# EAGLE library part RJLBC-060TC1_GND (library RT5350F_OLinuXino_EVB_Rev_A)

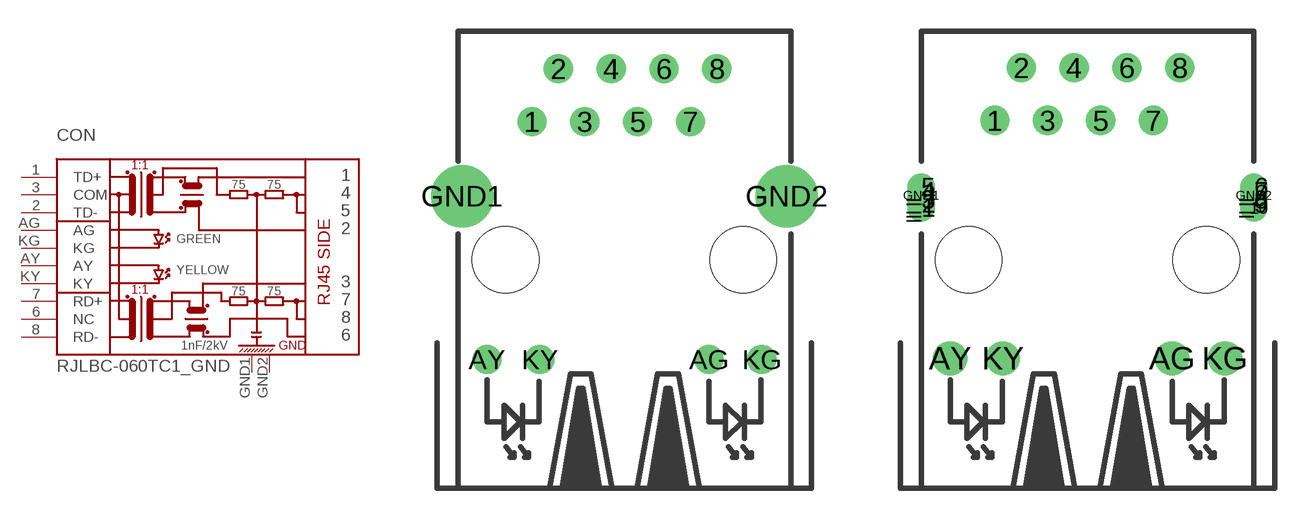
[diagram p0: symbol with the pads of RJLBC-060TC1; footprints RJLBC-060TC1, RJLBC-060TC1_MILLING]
Designator prefix CON

## RJLBC-060TC1_GND  [RJLBC-060TC1]
1  TD+
2  TD-
3  COM
6  NC
7  RD+
8  RD-
AG  AG  pas
AY  AY  pas
GND1  GND1  in
GND2  GND2  in
KG  KG  pas
KY  KY  pas

## RJLBC-060TC1_GND_MILLING  [RJLBC-060TC1_MILLING]
Pads as for RJLBC-060TC1

## Footprint RJLBC-060TC1 (pad centres in mm)
LAN traf & connector
drill 0.9: 1 -4.445,6.65; 2 -3.175,9.19; 3 -1.905,6.65; 4 -0.635,9.19; 5 0.635,6.65; 6 1.905,9.19; 7 3.175,6.65; 8 4.445,9.19; AG 4.07,-4.8; AY -6.61,-4.8; KG 6.61,-4.8; KY -4.07,-4.8
drill 2: GND1 -7.8,3.05; GND2 7.8,3.05
hole 3.2 at -5.715,0
hole 3.2 at 5.715,0
hole 3.2 at -5.715,0
hole 3.2 at 5.715,0

## Footprint RJLBC-060TC1_MILLING (pad centres in mm)
drill 0.9: 1 -4.455,6.7; 2 -3.185,9.24; 3 -1.915,6.7; 4 -0.645,9.24; 5 0.625,6.7; 6 1.895,9.24; 7 3.165,6.7; 8 4.435,9.24
drill 0.8: _1 -8,2.5; _2 -8,2.7; _3 -8,2.9; _4 -8,3.3; _5 -8,3.5; _6 8,3.5; _7 8,3.3; _8 8,2.9; _9 8,2.7; _10 8,2.5; GND1 -8,3.1; GND2 8,3.1
drill 1.1: AG 4.07,-4.748; AY -6.61,-4.748; KG 6.61,-4.748; KY -4.07,-4.748
hole 3.2 at -5.715,0
hole 3.2 at 5.715,0
hole 3.2 at -5.715,0
hole 3.2 at 5.715,0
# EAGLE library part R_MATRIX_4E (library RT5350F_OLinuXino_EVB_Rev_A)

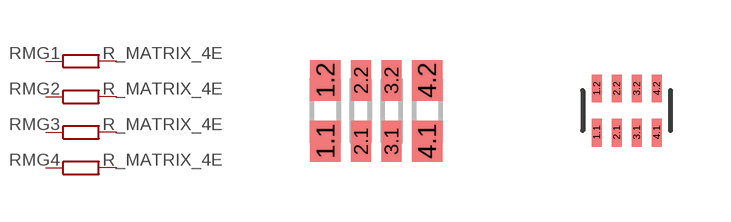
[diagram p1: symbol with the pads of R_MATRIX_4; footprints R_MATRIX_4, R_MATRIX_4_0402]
Designator prefix RM; gates G1=R_MARTIX G2=R_MARTIX G3=R_MARTIX G4=R_MARTIX

## R_MATRIX_4E  [R_MATRIX_4]
1.1  G1:1  pas
1.2  G1:2  pas
2.1  G2:1  pas
2.2  G2:2  pas
3.1  G3:1  pas
3.2  G3:2  pas
4.1  G4:1  pas
4.2  G4:2  pas

## R_MATRIX_4ER_MATRIX_4_0402  [R_MATRIX_4_0402]
Pads as for R_MATRIX_4

## R_MATRIX_4E_25X625  [R_MATRIX_4_0402_25X625]
Pads as for R_MATRIX_4

## R_MATRIX_4E_25X625_0R  [R_MATRIX_4_0402_25_625_0R]
Pads as for R_MATRIX_4

## Footprint R_MATRIX_4 (pad centres in mm)
Rotated counterclockwise 90 by Penko to ba as is in the real reel
smd 0.762 x 1.016: 1.1 -1.27,-0.762; 1.2 -1.27,0.762; 4.1 1.27,-0.762; 4.2 1.27,0.762
smd 0.508 x 1.016: 2.1 -0.381,-0.762; 2.2 -0.381,0.762; 3.1 0.381,-0.762; 3.2 0.381,0.762

## Footprint R_MATRIX_4_0402 (pad centres in mm)
Rotated counterclockwise 90 by Penko to ba as is in the real reel
smd 0.25 x 0.7: 1.1 -0.75,-0.55; 1.2 -0.75,0.55; 2.1 -0.25,-0.55; 2.2 -0.25,0.55; 3.1 0.25,-0.55; 3.2 0.25,0.55; 4.1 0.75,-0.55; 4.2 0.75,0.55

## Footprint R_MATRIX_4_0402_25X625 (pad centres in mm)
Rotated counterclockwise 90 by Penko to ba as is in the real reel
smd 0.25 x 0.625: 1.1 -0.75,-0.512; 1.2 -0.75,0.512; 2.1 -0.25,-0.512; 2.2 -0.25,0.512; 3.1 0.25,-0.512; 3.2 0.25,0.512; 4.1 0.75,-0.512; 4.2 0.75,0.512

## Footprint R_MATRIX_4_0402_25_625_0R (pad centres in mm)
Rotated counterclockwise 90 by Penko to ba as is in the real reel
smd 0.25 x 0.625: 1.1 -0.75,-0.512; 1.2 -0.75,0.512; 2.1 -0.25,-0.512; 2.2 -0.25,0.512; 3.1 0.25,-0.512; 3.2 0.25,0.512; 4.1 0.75,-0.512; 4.2 0.75,0.512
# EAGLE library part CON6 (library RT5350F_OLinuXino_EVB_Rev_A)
CONNECTORS - 6 PINS

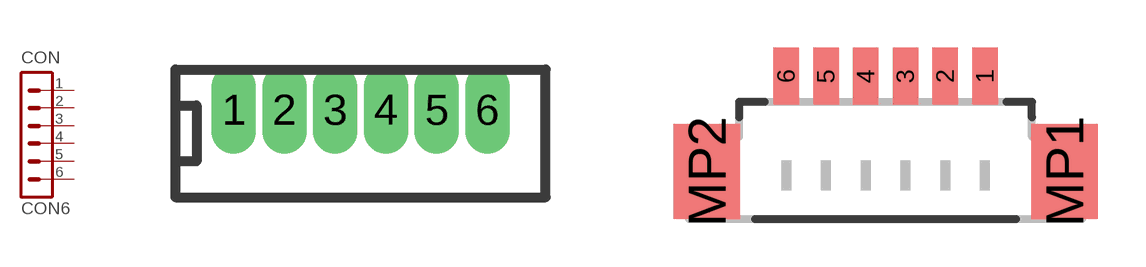
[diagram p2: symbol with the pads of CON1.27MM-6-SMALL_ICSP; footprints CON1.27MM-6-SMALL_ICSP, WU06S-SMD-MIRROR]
Designator prefix CON

## CON6  [CON1.27MM-6-SMALL_ICSP]
1  1  pas
2  2  pas
3  3  pas
4  4  pas
5  5  pas
6  6  pas

## CON6-WU06S-SMD  [WU06S-SMD-MIRROR]
Pads as for CON1.27MM-6-SMALL_ICSP

## CON61.27MM-6-SMALL  [CON1.27MM-6-SMALL_TRANSITIVE]
Pads as for CON1.27MM-6-SMALL_ICSP

## CON62.54-0-D  [CON2.54MM-6-0D]
Pads as for CON1.27MM-6-SMALL_ICSP

## CON6HD-515R_6P  [HD-515R_6P]
Pads as for CON1.27MM-6-SMALL_ICSP

## CON6HN1X6  [HN1X6]
Pads as for CON1.27MM-6-SMALL_ICSP

## CON6HN1X6-2.0(HN1X20-2.0)  [HN1X6-2.0]
Pads as for CON1.27MM-6-SMALL_ICSP

## CON6PN1X6  [PN1X6]
Pads as for CON1.27MM-6-SMALL_ICSP

## CON6PR6-3.96MM  [CON3.96MM-6-90]
Pads as for CON1.27MM-6-SMALL_ICSP

## CON6PV6-2.54MM  [CON2.54MM-6-0]
Pads as for CON1.27MM-6-SMALL_ICSP

## CON6PV6-3.96MM  [CON3.96MM-6-0]
Pads as for CON1.27MM-6-SMALL_ICSP

## CON6TDOCU  [CON6_TDOCU]
Pads as for CON1.27MM-6-SMALL_ICSP

## CON6TELEFON  [CON_TELEFON]
Pads as for CON1.27MM-6-SMALL_ICSP

## CON6WF6R  [WF6R]
Pads as for CON1.27MM-6-SMALL_ICSP

## CON6WF6S  [WF6S]
Pads as for CON1.27MM-6-SMALL_ICSP

## CON6WU06S-SMD  [WU06S-SMD]
Pads as for CON1.27MM-6-SMALL_ICSP

## CON6WUO6S  [WU06S]
Pads as for CON1.27MM-6-SMALL_ICSP

## Footprint CON1.27MM-6-SMALL_ICSP (pad centres in mm)
drill 0.6 pad 1.016 long: 1 -3.175,0; 2 -1.905,0; 3 -0.635,0; 4 0.635,0; 5 1.905,0; 6 3.175,0

## Footprint WU06S-SMD-MIRROR (pad centres in mm)
CI44 Series 1.25mm(.049") Pin Header Manifacture: CviLux, CI44 Series, Part Number: CI4406M1V00-LF Supplier: Comet Electronics Part Number: WU06S-SMD This is Male connector! It reqire SU06 Female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
smd 0.8 x 1.8: 1 3.125,0; 2 1.875,0; 3 0.625,0; 4 -0.625,0; 5 -1.875,0; 6 -3.125,0
smd 2.1 x 3: MP1 5.625,-3; MP2 -5.625,-3

## Footprint CON1.27MM-6-SMALL_TRANSITIVE (pad centres in mm)
drill 0.6 pad 1.016 long: 1 3.175,0; 2 1.905,0; 3 0.635,0; 4 -0.635,0; 5 -1.905,0; 6 -3.175,0

## Footprint CON2.54MM-6-0D (pad centres in mm)
drill 1.092 pad 1.778 square: 1 -6.35,0
drill 1.092 pad 1.778: 2 -3.81,0; 3 -1.27,0; 4 1.27,0; 5 3.81,0; 6 6.35,0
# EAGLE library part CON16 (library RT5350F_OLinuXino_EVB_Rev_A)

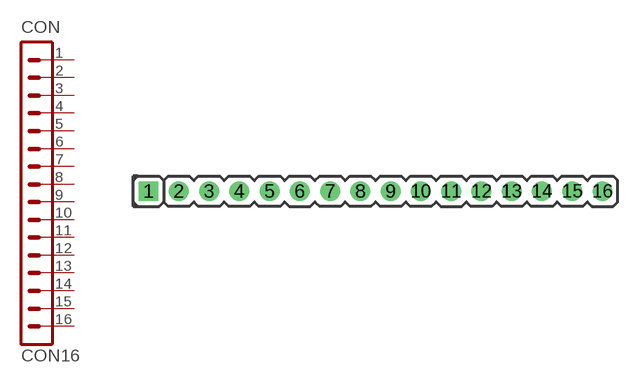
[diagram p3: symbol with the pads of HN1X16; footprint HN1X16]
Designator prefix CON

## CON16-HN1X16  [HN1X16]
1  1  pas
2  2  pas
3  3  pas
4  4  pas
5  5  pas
6  6  pas
7  7  pas
8  8  pas
9  9  pas
10  10  pas
11  11  pas
12  12  pas
13  13  pas
14  14  pas
15  15  pas
16  16  pas

## Footprint HN1X16 (pad centres in mm)
CH31 Series Manufacture: CviLux Supplier: Comet Electronics Part Number: HN1x16 is part of HN1x40 This is Male connector! It reqires PN1x16 Female connector Eletrical Characteristics: - 3A(per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
drill 1.016 pad 1.676 square: 1 -17.78,0
drill 1.016 pad 1.676: 2 -15.24,0; 3 -12.7,0; 4 -10.16,0; 5 -7.62,0; 6 -5.08,0; 7 -2.54,0; 8 0,0; 9 2.54,0; 10 5.08,0; 11 7.62,0; 12 10.16,0; 13 12.7,0; 14 15.24,0; 15 17.78,0; 16 20.32,0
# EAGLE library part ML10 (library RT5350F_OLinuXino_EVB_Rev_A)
HARTING

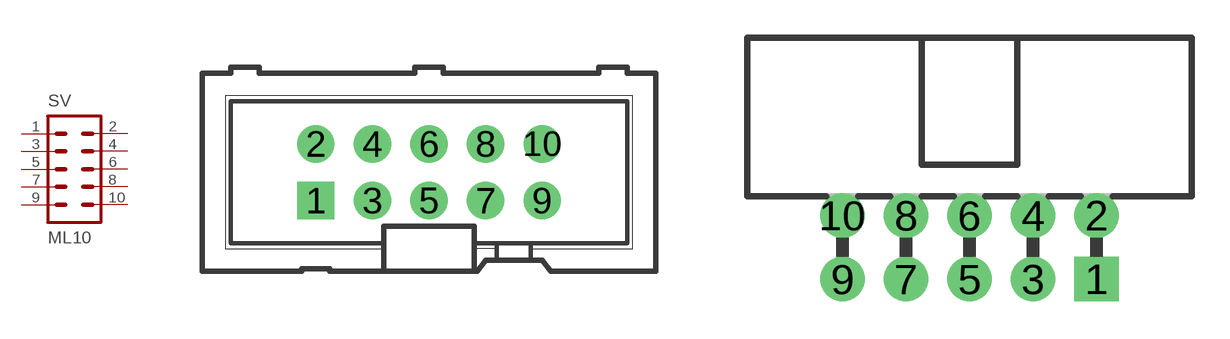
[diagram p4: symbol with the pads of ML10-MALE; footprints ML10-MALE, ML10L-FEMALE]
Designator prefix SV

## ML10  [ML10-MALE]
1  1  pas
2  2  pas
3  3  pas
4  4  pas
5  5  pas
6  6  pas
7  7  pas
8  8  pas
9  9  pas
10  10  pas

## ML10"  [ML10L-FEMALE]
Pads as for ML10-MALE

## ML10-3M  [3M_10]
Pads as for ML10-MALE

## ML10-3ML  [3M_10L]
Pads as for ML10-MALE

## ML10-GPH127SMT-02X05(PA-V16X-2X5-LF)  [GPH127SMT-02X05(PA-V16X-2X5-LF)]
Pads as for ML10-MALE

## ML10F50  [ML10_50MILS_F]
Pads as for ML10-MALE

## ML10L  [ML10L]
Pads as for ML10-MALE

## ML10M50  [ML10_50MILS_M]
Pads as for ML10-MALE

## ML10MD  [ML10_S]
Pads as for ML10-MALE

## ML10ML10-FEMALE  [ML10-FEMALE]
Pads as for ML10-MALE

## ML10ML10-FEMALE(IDC10S/PCB)  [ML10-FEMALE(IDC10S/PCB)]
Pads as for ML10-MALE

## ML10ML10M  [ML10_MIRROR]
Pads as for ML10-MALE

## ML10ML10_NEW  [ML10_NEW]
Pads as for ML10-MALE

## ML10PA-V16X-2X5-LF_0.60_DRILL  [PA-V16X-2X5-LF_0.60_DRILL]
Pads as for ML10-MALE

## ML10PA-V16X-2X5-LF_0.65_DRILL  [PA-V16X-2X5-LF_0.65_DRILL]
Pads as for ML10-MALE

## ML10R  [BH10R]
Pads as for ML10-MALE

## ML10SMD  [ML10_PADS]
Pads as for ML10-MALE

## ML10SMD_1  [ML10L_PADS_FEMAIL]
Pads as for ML10-MALE

## ML10YA-V36P-2X5-LF  [YA-V36P-2X5-LF]
Pads as for ML10-MALE

## ML10YA-V36P-2X5-LF_0.60_DRILL  [YA-V36P-2X5-LF_0.60_DRILL]
Pads as for ML10-MALE

## ML10YA-V36P-LF_0.65_DRILL  [YA-V36P-2X5-LF_0.65_DRILL]
Pads as for ML10-MALE

## Footprint ML10-MALE (pad centres in mm)
HARTING
drill 1.1 pad 1.676 square: 1 -5.08,-1.27
drill 1.1 pad 1.676: 2 -5.08,1.27; 3 -2.54,-1.27; 4 -2.54,1.27; 5 0,-1.27; 6 0,1.27; 7 2.54,-1.27; 8 2.54,1.27; 9 5.08,-1.27; 10 5.08,1.27

## Footprint ML10L-FEMALE (pad centres in mm)
drill 1 pad 1.778 square: 1 5.08,-6.35
drill 1 pad 1.778: 2 5.08,-3.81; 3 2.54,-6.35; 4 2.54,-3.81; 5 0,-6.35; 6 0,-3.81; 7 -2.54,-6.35; 8 -2.54,-3.81; 9 -5.08,-6.35; 10 -5.08,-3.81

## Footprint 3M_10 (pad centres in mm)
3M
drill 0.813 square: 1 -5.08,-1.27; 2 -5.08,1.27; 3 -2.54,-1.27; 4 -2.54,1.27; 5 0,-1.27; 6 0,1.27; 7 2.54,-1.27; 8 2.54,1.27; 9 5.08,-1.27; 10 5.08,1.27

## Footprint 3M_10L (pad centres in mm)
3M
drill 0.813 square: 1 -5.08,-5.08; 2 -5.08,-2.54; 3 -2.54,-5.08; 4 -2.54,-2.54; 5 0,-5.08; 6 0,-2.54; 7 2.54,-5.08; 8 2.54,-2.54; 9 5.08,-5.08; 10 5.08,-2.54
hole 2.54 at -10.998,-3.277
hole 2.54 at 10.998,-3.277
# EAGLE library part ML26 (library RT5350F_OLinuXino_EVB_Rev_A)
HARTING

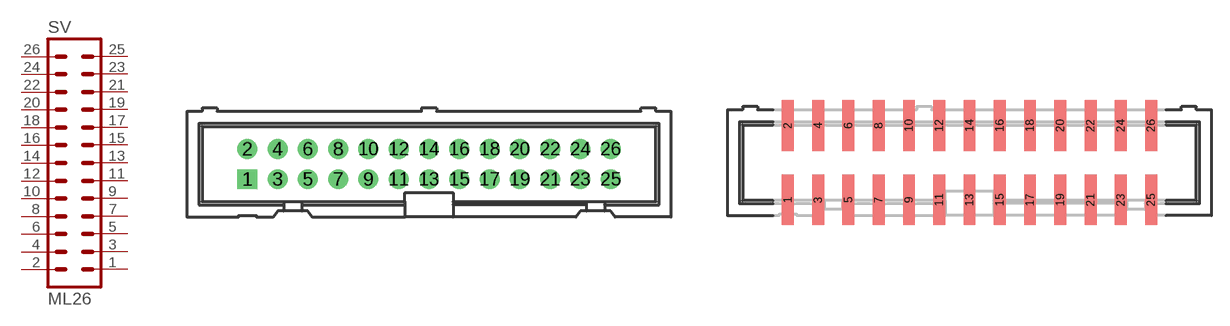
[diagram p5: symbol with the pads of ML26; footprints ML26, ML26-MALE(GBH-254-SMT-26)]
Designator prefix SV

## ML26  [ML26]
1  1  pas
2  2  pas
3  3  pas
4  4  pas
5  5  pas
6  6  pas
7  7  pas
8  8  pas
9  9  pas
10  10  pas
11  11  pas
12  12  pas
13  13  pas
14  14  pas
15  15  pas
16  16  pas
17  17  pas
18  18  pas
19  19  pas
20  20  pas
21  21  pas
22  22  pas
23  23  pas
24  24  pas
25  25  pas
26  26  pas

## ML26-(GBH-254-SMT-26)  [ML26-MALE(GBH-254-SMT-26)]
Pads as for ML26

## ML263M  [3M_26]
Pads as for ML26

## ML263ML  [3M_26L]
Pads as for ML26

## ML26HN2X13  [HN2X13-MALE]
Pads as for ML26

## ML26IDC26S/PCB  [ML26-FEMALE(IDC26S/PCB)]
Pads as for ML26

## ML26IDC26S/PCB_PADS  [ML26L_PADS-FEMALE(IDC26S/PCB)]
Pads as for ML26

## ML26L  [ML26L]
Pads as for ML26

## ML26PN2X13  [PN2X13]
Pads as for ML26

## ML26R  [BH26R]
Pads as for ML26

## Footprint ML26 (pad centres in mm)
HARTING
drill 1.016 pad 1.676 square: 1 -15.24,-1.27
drill 1.016 pad 1.676: 2 -15.24,1.27; 3 -12.7,-1.27; 4 -12.7,1.27; 5 -10.16,-1.27; 6 -10.16,1.27; 7 -7.62,-1.27; 8 -7.62,1.27; 9 -5.08,-1.27; 10 -5.08,1.27; 11 -2.54,-1.27; 12 -2.54,1.27; 13 0,-1.27; 14 0,1.27; 15 2.54,-1.27; 16 2.54,1.27; 17 5.08,-1.27; 18 5.08,1.27; 19 7.62,-1.27; 20 7.62,1.27; 21 10.16,-1.27; 22 10.16,1.27; 23 12.7,-1.27; 24 12.7,1.27; 25 15.24,-1.27; 26 15.24,1.27

## Footprint ML26-MALE(GBH-254-SMT-26) (pad centres in mm)
smd 1 x 4.25: 1 -15.24,-3.125; 2 -15.24,3.125; 3 -12.7,-3.125; 4 -12.7,3.125; 5 -10.16,-3.125; 6 -10.16,3.125; 7 -7.62,-3.125; 8 -7.62,3.125; 9 -5.08,-3.125; 10 -5.08,3.125; 11 -2.54,-3.125; 12 -2.54,3.125; 13 0,-3.125; 14 0,3.125; 15 2.54,-3.125; 16 2.54,3.125; 17 5.08,-3.125; 18 5.08,3.125; 19 7.62,-3.125; 20 7.62,3.125; 21 10.16,-3.125; 22 10.16,3.125; 23 12.7,-3.125; 24 12.7,3.125; 25 15.24,-3.125; 26 15.24,3.125

## Footprint 3M_26 (pad centres in mm)
3M
drill 0.813 square: 1 -15.24,-1.27; 2 -15.24,1.27; 3 -12.7,-1.27; 4 -12.7,1.27; 5 -10.16,-1.27; 6 -10.16,1.27; 7 -7.62,-1.27; 8 -7.62,1.27; 9 -5.08,-1.27; 10 -5.08,1.27; 11 -2.54,-1.27; 12 -2.54,1.27; 13 0,-1.27; 14 0,1.27; 15 2.54,-1.27; 16 2.54,1.27; 17 5.08,-1.27; 18 5.08,1.27; 19 7.62,-1.27; 20 7.62,1.27; 21 10.16,-1.27; 22 10.16,1.27; 23 12.7,-1.27; 24 12.7,1.27; 25 15.24,-1.27; 26 15.24,1.27

## Footprint 3M_26L (pad centres in mm)
3M
drill 0.813 square: 1 -15.24,-5.08; 2 -15.24,-2.54; 3 -12.7,-5.08; 4 -12.7,-2.54; 5 -10.16,-5.08; 6 -10.16,-2.54; 7 -7.62,-5.08; 8 -7.62,-2.54; 9 -5.08,-5.08; 10 -5.08,-2.54; 11 -2.54,-5.08; 12 -2.54,-2.54; 13 0,-5.08; 14 0,-2.54; 15 2.54,-5.08; 16 2.54,-2.54; 17 5.08,-5.08; 18 5.08,-2.54; 19 7.62,-5.08; 20 7.62,-2.54; 21 10.16,-5.08; 22 10.16,-2.54; 23 12.7,-5.08; 24 12.7,-2.54; 25 15.24,-5.08; 26 15.24,-2.54
hole 2.54 at -21.158,-3.277
hole 2.54 at 21.158,-3.277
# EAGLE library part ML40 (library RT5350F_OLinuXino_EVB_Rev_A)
HARTING

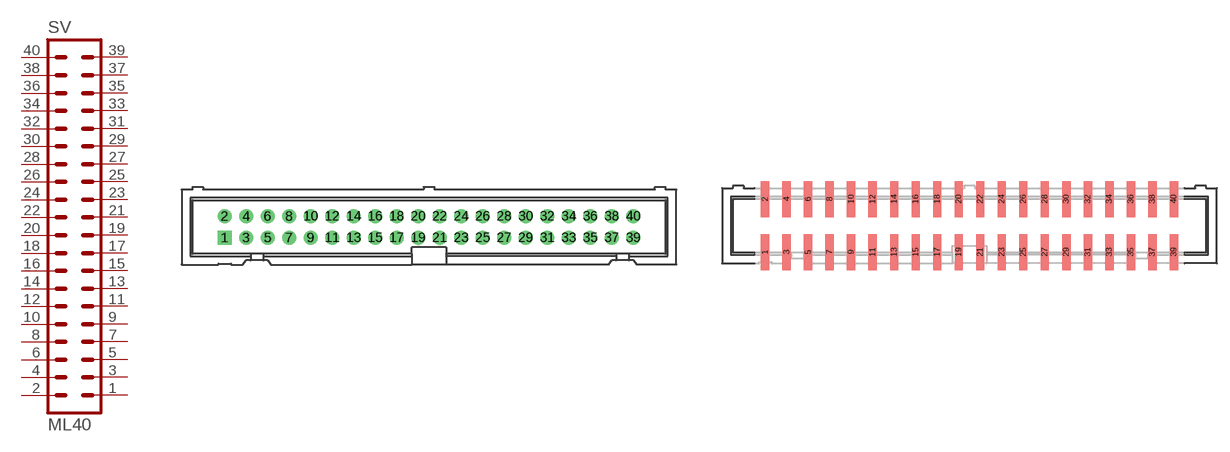
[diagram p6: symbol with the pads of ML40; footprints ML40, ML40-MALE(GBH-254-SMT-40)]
Designator prefix SV

## ML40  [ML40]
1  1  pas
2  2  pas
3  3  pas
4  4  pas
5  5  pas
6  6  pas
7  7  pas
8  8  pas
9  9  pas
10  10  pas
11  11  pas
12  12  pas
13  13  pas
14  14  pas
15  15  pas
16  16  pas
17  17  pas
18  18  pas
19  19  pas
20  20  pas
21  21  pas
22  22  pas
23  23  pas
24  24  pas
25  25  pas
26  26  pas
27  27  pas
28  28  pas
29  29  pas
30  30  pas
31  31  pas
32  32  pas
33  33  pas
34  34  pas
35  35  pas
36  36  pas
37  37  pas
38  38  pas
39  39  pas
40  40  pas

## ML40-GBH-254-SMT-40  [ML40-MALE(GBH-254-SMT-40)]
Pads as for ML40

## ML40-GPH127SMT-02X20(PA-V16X-2X20-LF)  [GPH127SMT-02X20(PA-V16X-2X20-LF)]
Pads as for ML40

## ML403M  [3M_40]
Pads as for ML40

## ML403ML  [3M_40L]
Pads as for ML40

## ML40F-V50X-2X20-LF  [F-V50X-2X20-LF]
Pads as for ML40

## ML40F-V50X-2X20-LF(FIX)  [F-V50X-2X20-LF(FIX)]
Pads as for ML40

## ML40F50  [ML40_50MILS_F]
Pads as for ML40

## ML40HN2X20  [HN2X20-MALE]
Pads as for ML40

## ML40L  [ML40L]
Pads as for ML40

## ML40M50  [ML40_50MILS_M]
Pads as for ML40

## ML40ML40L_SMD_(PN2X20)  [ML40L_PADS_FEMALE]
Pads as for ML40

## ML40ML40_FEMALE  [ML40-FEMALE]
Pads as for ML40

## ML40ML40_PADS  [ML40_PADS]
Pads as for ML40

## ML40PA-V16X-2X20-LF_0.60_DRILL  [PA-V16X-2X20-LF_0.60_DRILL]
Pads as for ML40

## ML40PA-V16X-2X20-LF_0.65_DRILL  [PA-V16X-2X20-LF_0.65_DRILL]
Pads as for ML40

## ML40PN2X20  [ML40-FEMALE(PN2X20)]
Pads as for ML40

## ML40R  [BH40R]
Pads as for ML40

## ML40THIN_PADS  [ML40_50MIL_M_THIN_PADS]
Pads as for ML40

## ML40YA-V36-2X20-LF_0.65_DRILL  [YA-V36P-2X20-LF_0.65_DRILL]
Pads as for ML40

## ML40YA-V36P-2X20-LF  [YA-V36P-2X20-LF]
Pads as for ML40

## ML40YA-V36P-2X20-LF_0.60_DRILL  [YA-V36P-2X20-LF_0.60_DRILL]
Pads as for ML40

## Footprint ML40 (pad centres in mm)
HARTING
drill 1.016 pad 1.676 square: 1 -24.13,-1.27
drill 1.016 pad 1.676: 2 -24.13,1.27; 3 -21.59,-1.27; 4 -21.59,1.27; 5 -19.05,-1.27; 6 -19.05,1.27; 7 -16.51,-1.27; 8 -16.51,1.27; 9 -13.97,-1.27; 10 -13.97,1.27; 11 -11.43,-1.27; 12 -11.43,1.27; 13 -8.89,-1.27; 14 -8.89,1.27; 15 -6.35,-1.27; 16 -6.35,1.27; 17 -3.81,-1.27; 18 -3.81,1.27; 19 -1.27,-1.27; 20 -1.27,1.27; 21 1.27,-1.27; 22 1.27,1.27; 23 3.81,-1.27; 24 3.81,1.27; 25 6.35,-1.27; 26 6.35,1.27; 27 8.89,-1.27; 28 8.89,1.27; 29 11.43,-1.27; 30 11.43,1.27; 31 13.97,-1.27; 32 13.97,1.27; 33 16.51,-1.27; 34 16.51,1.27; 35 19.05,-1.27; 36 19.05,1.27; 37 21.59,-1.27; 38 21.59,1.27; 39 24.13,-1.27; 40 24.13,1.27

## Footprint ML40-MALE(GBH-254-SMT-40) (pad centres in mm)
smd 1 x 4.25: 1 -24.13,-3.125; 2 -24.13,3.125; 3 -21.59,-3.125; 4 -21.59,3.125; 5 -19.05,-3.125; 6 -19.05,3.125; 7 -16.51,-3.125; 8 -16.51,3.125; 9 -13.97,-3.125; 10 -13.97,3.125; 11 -11.43,-3.125; 12 -11.43,3.125; 13 -8.89,-3.125; 14 -8.89,3.125; 15 -6.35,-3.125; 16 -6.35,3.125; 17 -3.81,-3.125; 18 -3.81,3.125; 19 -1.27,-3.125; 20 -1.27,3.125; 21 1.27,-3.125; 22 1.27,3.125; 23 3.81,-3.125; 24 3.81,3.125; 25 6.35,-3.125; 26 6.35,3.125; 27 8.89,-3.125; 28 8.89,3.125; 29 11.43,-3.125; 30 11.43,3.125; 31 13.97,-3.125; 32 13.97,3.125; 33 16.51,-3.125; 34 16.51,3.125; 35 19.05,-3.125; 36 19.05,3.125; 37 21.59,-3.125; 38 21.59,3.125; 39 24.13,-3.125; 40 24.13,3.125

## Footprint GPH127SMT-02X20(PA-V16X-2X20-LF) (pad centres in mm)
male
smd 0.7 x 1.8: 1 -12.065,-2.032; 2 -12.065,2.032; 3 -10.795,-2.032; 4 -10.795,2.032; 5 -9.525,-2.032; 6 -9.525,2.032; 7 -8.255,-2.032; 8 -8.255,2.032; 9 -6.985,-2.032; 10 -6.985,2.032; 11 -5.715,-2.032; 12 -5.715,2.032; 13 -4.445,-2.032; 14 -4.445,2.032; 15 -3.175,-2.032; 16 -3.175,2.032; 17 -1.905,-2.032; 18 -1.905,2.032; 19 -0.635,-2.032; 20 -0.635,2.032; 21 0.635,-2.032; 22 0.635,2.032; 23 1.905,-2.032; 24 1.905,2.032; 25 3.175,-2.032; 26 3.175,2.032; 27 4.445,-2.032; 28 4.445,2.032; 29 5.715,-2.032; 30 5.715,2.032; 31 6.985,-2.032; 32 6.985,2.032; 33 8.255,-2.032; 34 8.255,2.032; 35 9.525,-2.032; 36 9.525,2.032; 37 10.795,-2.032; 38 10.795,2.032; 39 12.065,-2.032; 40 12.065,2.032
hole 0.7 at -11.43,0
hole 0.7 at 11.43,0

## Footprint 3M_40 (pad centres in mm)
3M
drill 0.813 square: 1 -24.13,-1.27; 2 -24.13,1.27; 3 -21.59,-1.27; 4 -21.59,1.27; 5 -19.05,-1.27; 6 -19.05,1.27; 7 -16.51,-1.27; 8 -16.51,1.27; 9 -13.97,-1.27; 10 -13.97,1.27; 11 -11.43,-1.27; 12 -11.43,1.27; 13 -8.89,-1.27; 14 -8.89,1.27; 15 -6.35,-1.27; 16 -6.35,1.27; 17 -3.81,-1.27; 18 -3.81,1.27; 19 -1.27,-1.27; 20 -1.27,1.27; 21 1.27,-1.27; 22 1.27,1.27; 23 3.81,-1.27; 24 3.81,1.27; 25 6.35,-1.27; 26 6.35,1.27; 27 8.89,-1.27; 28 8.89,1.27; 29 11.43,-1.27; 30 11.43,1.27; 31 13.97,-1.27; 32 13.97,1.27; 33 16.51,-1.27; 34 16.51,1.27; 35 19.05,-1.27; 36 19.05,1.27; 37 21.59,-1.27; 38 21.59,1.27; 39 24.13,-1.27; 40 24.13,1.27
